VERSION 5.7 ;
  NOWIREEXTENSIONATPIN ON ;
  DIVIDERCHAR "/" ;
  BUSBITCHARS "[]" ;
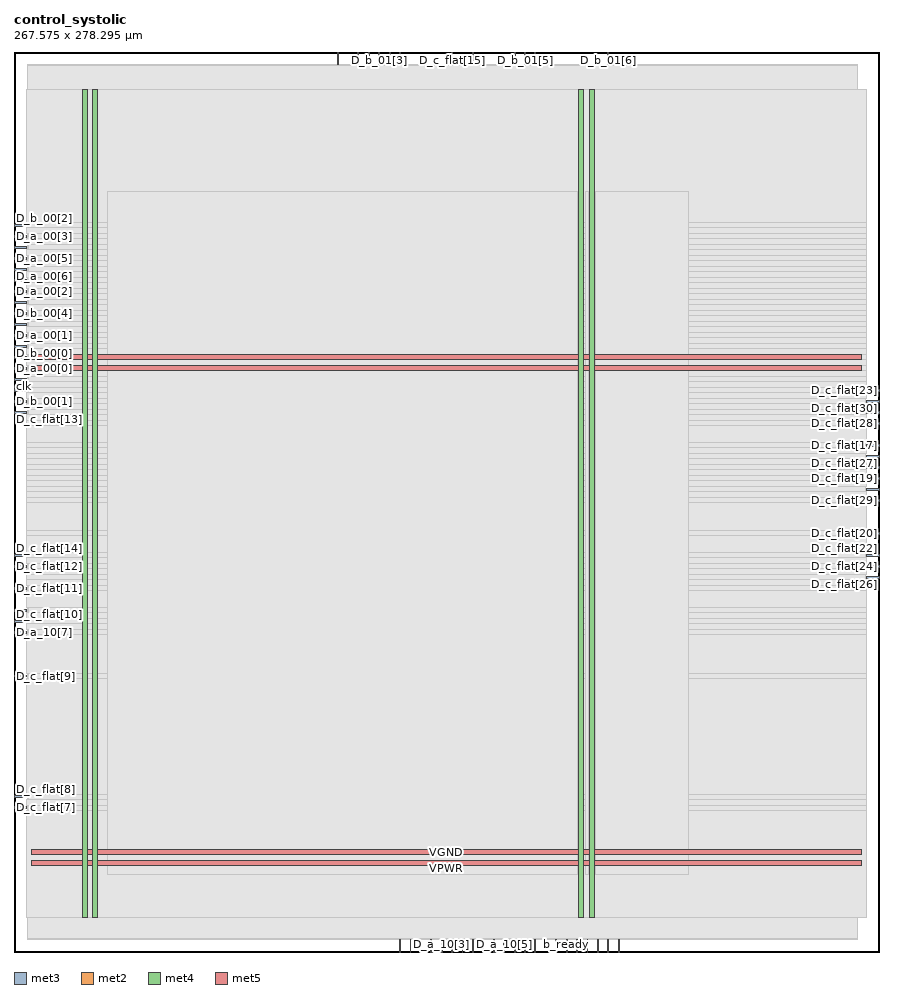
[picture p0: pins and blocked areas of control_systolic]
MACRO control_systolic
  CLASS BLOCK ;
  FOREIGN control_systolic ;
  ORIGIN 0.000 0.000 ;
  SIZE 267.575 BY 278.295 ;
  PIN D_a_00[0]
    DIRECTION INPUT ;
    USE SIGNAL ;
    ANTENNAGATEAREA 0.196500 ;
    PORT
      LAYER met3 ;
        RECT 0.000 180.240 4.000 180.840 ;
    END
  END D_a_00[0]
  PIN D_a_00[1]
    DIRECTION INPUT ;
    USE SIGNAL ;
    ANTENNAGATEAREA 0.196500 ;
    PORT
      LAYER met3 ;
        RECT 0.000 190.440 4.000 191.040 ;
    END
  END D_a_00[1]
  PIN D_a_00[2]
    DIRECTION INPUT ;
    USE SIGNAL ;
    ANTENNAGATEAREA 0.196500 ;
    PORT
      LAYER met3 ;
        RECT 0.000 204.040 4.000 204.640 ;
    END
  END D_a_00[2]
  PIN D_a_00[3]
    DIRECTION INPUT ;
    USE SIGNAL ;
    ANTENNAGATEAREA 0.196500 ;
    PORT
      LAYER met3 ;
        RECT 0.000 221.040 4.000 221.640 ;
    END
  END D_a_00[3]
  PIN D_a_00[4]
    DIRECTION INPUT ;
    USE SIGNAL ;
    ANTENNAGATEAREA 0.196500 ;
    PORT
      LAYER met3 ;
        RECT 0.000 217.640 4.000 218.240 ;
    END
  END D_a_00[4]
  PIN D_a_00[5]
    DIRECTION INPUT ;
    USE SIGNAL ;
    ANTENNAGATEAREA 0.196500 ;
    PORT
      LAYER met3 ;
        RECT 0.000 214.240 4.000 214.840 ;
    END
  END D_a_00[5]
  PIN D_a_00[6]
    DIRECTION INPUT ;
    USE SIGNAL ;
    ANTENNAGATEAREA 0.196500 ;
    PORT
      LAYER met3 ;
        RECT 0.000 210.840 4.000 211.440 ;
    END
  END D_a_00[6]
  PIN D_a_00[7]
    DIRECTION INPUT ;
    USE SIGNAL ;
    ANTENNAGATEAREA 0.196500 ;
    PORT
      LAYER met2 ;
        RECT 99.910 274.295 100.190 278.295 ;
    END
  END D_a_00[7]
  PIN D_a_10[0]
    DIRECTION INPUT ;
    USE SIGNAL ;
    ANTENNAGATEAREA 0.196500 ;
    PORT
      LAYER met2 ;
        RECT 148.210 0.000 148.490 4.000 ;
    END
  END D_a_10[0]
  PIN D_a_10[1]
    DIRECTION INPUT ;
    USE SIGNAL ;
    ANTENNAGATEAREA 0.196500 ;
    PORT
      LAYER met2 ;
        RECT 141.770 0.000 142.050 4.000 ;
    END
  END D_a_10[1]
  PIN D_a_10[2]
    DIRECTION INPUT ;
    USE SIGNAL ;
    ANTENNAGATEAREA 0.196500 ;
    PORT
      LAYER met2 ;
        RECT 128.890 0.000 129.170 4.000 ;
    END
  END D_a_10[2]
  PIN D_a_10[3]
    DIRECTION INPUT ;
    USE SIGNAL ;
    ANTENNAGATEAREA 0.196500 ;
    PORT
      LAYER met2 ;
        RECT 132.110 0.000 132.390 4.000 ;
    END
  END D_a_10[3]
  PIN D_a_10[4]
    DIRECTION INPUT ;
    USE SIGNAL ;
    ANTENNAGATEAREA 0.196500 ;
    PORT
      LAYER met2 ;
        RECT 135.330 0.000 135.610 4.000 ;
    END
  END D_a_10[4]
  PIN D_a_10[5]
    DIRECTION INPUT ;
    USE SIGNAL ;
    ANTENNAGATEAREA 0.196500 ;
    PORT
      LAYER met2 ;
        RECT 151.430 0.000 151.710 4.000 ;
    END
  END D_a_10[5]
  PIN D_a_10[6]
    DIRECTION INPUT ;
    USE SIGNAL ;
    ANTENNAGATEAREA 0.196500 ;
    PORT
      LAYER met2 ;
        RECT 157.870 0.000 158.150 4.000 ;
    END
  END D_a_10[6]
  PIN D_a_10[7]
    DIRECTION INPUT ;
    USE SIGNAL ;
    ANTENNAGATEAREA 0.196500 ;
    PORT
      LAYER met3 ;
        RECT 0.000 98.640 4.000 99.240 ;
    END
  END D_a_10[7]
  PIN D_b_00[0]
    DIRECTION INPUT ;
    USE SIGNAL ;
    ANTENNAGATEAREA 0.196500 ;
    PORT
      LAYER met3 ;
        RECT 0.000 187.040 4.000 187.640 ;
    END
  END D_b_00[0]
  PIN D_b_00[1]
    DIRECTION INPUT ;
    USE SIGNAL ;
    ANTENNAGATEAREA 0.196500 ;
    PORT
      LAYER met3 ;
        RECT 0.000 170.040 4.000 170.640 ;
    END
  END D_b_00[1]
  PIN D_b_00[2]
    DIRECTION INPUT ;
    USE SIGNAL ;
    ANTENNAGATEAREA 0.196500 ;
    PORT
      LAYER met3 ;
        RECT 0.000 224.440 4.000 225.040 ;
    END
  END D_b_00[2]
  PIN D_b_00[3]
    DIRECTION INPUT ;
    USE SIGNAL ;
    ANTENNAGATEAREA 0.196500 ;
    PORT
      LAYER met3 ;
        RECT 0.000 207.440 4.000 208.040 ;
    END
  END D_b_00[3]
  PIN D_b_00[4]
    DIRECTION INPUT ;
    USE SIGNAL ;
    ANTENNAGATEAREA 0.196500 ;
    PORT
      LAYER met3 ;
        RECT 0.000 197.240 4.000 197.840 ;
    END
  END D_b_00[4]
  PIN D_b_00[5]
    DIRECTION INPUT ;
    USE SIGNAL ;
    ANTENNAGATEAREA 0.196500 ;
    PORT
      LAYER met3 ;
        RECT 0.000 193.840 4.000 194.440 ;
    END
  END D_b_00[5]
  PIN D_b_00[6]
    DIRECTION INPUT ;
    USE SIGNAL ;
    ANTENNAGATEAREA 0.196500 ;
    PORT
      LAYER met3 ;
        RECT 0.000 183.640 4.000 184.240 ;
    END
  END D_b_00[6]
  PIN D_b_00[7]
    DIRECTION INPUT ;
    USE SIGNAL ;
    ANTENNAGATEAREA 0.196500 ;
    PORT
      LAYER met3 ;
        RECT 0.000 200.640 4.000 201.240 ;
    END
  END D_b_00[7]
  PIN D_b_01[0]
    DIRECTION INPUT ;
    USE SIGNAL ;
    ANTENNAGATEAREA 0.196500 ;
    PORT
      LAYER met2 ;
        RECT 109.570 274.295 109.850 278.295 ;
    END
  END D_b_01[0]
  PIN D_b_01[1]
    DIRECTION INPUT ;
    USE SIGNAL ;
    ANTENNAGATEAREA 0.196500 ;
    PORT
      LAYER met2 ;
        RECT 106.350 274.295 106.630 278.295 ;
    END
  END D_b_01[1]
  PIN D_b_01[2]
    DIRECTION INPUT ;
    USE SIGNAL ;
    ANTENNAGATEAREA 0.196500 ;
    PORT
      LAYER met2 ;
        RECT 119.230 274.295 119.510 278.295 ;
    END
  END D_b_01[2]
  PIN D_b_01[3]
    DIRECTION INPUT ;
    USE SIGNAL ;
    ANTENNAGATEAREA 0.196500 ;
    PORT
      LAYER met2 ;
        RECT 112.790 274.295 113.070 278.295 ;
    END
  END D_b_01[3]
  PIN D_b_01[4]
    DIRECTION INPUT ;
    USE SIGNAL ;
    ANTENNAGATEAREA 0.196500 ;
    PORT
      LAYER met2 ;
        RECT 116.010 274.295 116.290 278.295 ;
    END
  END D_b_01[4]
  PIN D_b_01[5]
    DIRECTION INPUT ;
    USE SIGNAL ;
    ANTENNAGATEAREA 0.196500 ;
    PORT
      LAYER met2 ;
        RECT 157.870 274.295 158.150 278.295 ;
    END
  END D_b_01[5]
  PIN D_b_01[6]
    DIRECTION INPUT ;
    USE SIGNAL ;
    ANTENNAGATEAREA 0.196500 ;
    PORT
      LAYER met2 ;
        RECT 183.630 274.295 183.910 278.295 ;
    END
  END D_b_01[6]
  PIN D_b_01[7]
    DIRECTION INPUT ;
    USE SIGNAL ;
    ANTENNAGATEAREA 0.196500 ;
    PORT
      LAYER met2 ;
        RECT 154.650 274.295 154.930 278.295 ;
    END
  END D_b_01[7]
  PIN D_c_flat[0]
    DIRECTION OUTPUT ;
    USE SIGNAL ;
    ANTENNADIFFAREA 0.445500 ;
    PORT
      LAYER met2 ;
        RECT 138.550 0.000 138.830 4.000 ;
    END
  END D_c_flat[0]
  PIN D_c_flat[10]
    DIRECTION OUTPUT ;
    USE SIGNAL ;
    ANTENNADIFFAREA 0.445500 ;
    PORT
      LAYER met3 ;
        RECT 0.000 102.040 4.000 102.640 ;
    END
  END D_c_flat[10]
  PIN D_c_flat[11]
    DIRECTION OUTPUT ;
    USE SIGNAL ;
    ANTENNADIFFAREA 0.445500 ;
    PORT
      LAYER met3 ;
        RECT 0.000 112.240 4.000 112.840 ;
    END
  END D_c_flat[11]
  PIN D_c_flat[12]
    DIRECTION OUTPUT ;
    USE SIGNAL ;
    ANTENNADIFFAREA 0.445500 ;
    PORT
      LAYER met3 ;
        RECT 0.000 119.040 4.000 119.640 ;
    END
  END D_c_flat[12]
  PIN D_c_flat[13]
    DIRECTION OUTPUT ;
    USE SIGNAL ;
    ANTENNADIFFAREA 0.445500 ;
    PORT
      LAYER met3 ;
        RECT 0.000 166.640 4.000 167.240 ;
    END
  END D_c_flat[13]
  PIN D_c_flat[14]
    DIRECTION OUTPUT ;
    USE SIGNAL ;
    ANTENNADIFFAREA 0.445500 ;
    PORT
      LAYER met3 ;
        RECT 0.000 122.440 4.000 123.040 ;
    END
  END D_c_flat[14]
  PIN D_c_flat[15]
    DIRECTION OUTPUT ;
    USE SIGNAL ;
    ANTENNADIFFAREA 0.445500 ;
    PORT
      LAYER met2 ;
        RECT 135.330 274.295 135.610 278.295 ;
    END
  END D_c_flat[15]
  PIN D_c_flat[16]
    DIRECTION OUTPUT ;
    USE SIGNAL ;
    ANTENNADIFFAREA 0.445500 ;
    PORT
      LAYER met3 ;
        RECT 263.575 149.640 267.575 150.240 ;
    END
  END D_c_flat[16]
  PIN D_c_flat[17]
    DIRECTION OUTPUT ;
    USE SIGNAL ;
    ANTENNADIFFAREA 0.445500 ;
    PORT
      LAYER met3 ;
        RECT 263.575 156.440 267.575 157.040 ;
    END
  END D_c_flat[17]
  PIN D_c_flat[18]
    DIRECTION OUTPUT ;
    USE SIGNAL ;
    ANTENNADIFFAREA 0.445500 ;
    PORT
      LAYER met2 ;
        RECT 141.770 274.295 142.050 278.295 ;
    END
  END D_c_flat[18]
  PIN D_c_flat[19]
    DIRECTION OUTPUT ;
    USE SIGNAL ;
    ANTENNADIFFAREA 0.445500 ;
    PORT
      LAYER met3 ;
        RECT 263.575 146.240 267.575 146.840 ;
    END
  END D_c_flat[19]
  PIN D_c_flat[1]
    DIRECTION OUTPUT ;
    USE SIGNAL ;
    ANTENNADIFFAREA 0.445500 ;
    PORT
      LAYER met2 ;
        RECT 144.990 0.000 145.270 4.000 ;
    END
  END D_c_flat[1]
  PIN D_c_flat[20]
    DIRECTION OUTPUT ;
    USE SIGNAL ;
    ANTENNADIFFAREA 0.445500 ;
    PORT
      LAYER met3 ;
        RECT 263.575 129.240 267.575 129.840 ;
    END
  END D_c_flat[20]
  PIN D_c_flat[21]
    DIRECTION OUTPUT ;
    USE SIGNAL ;
    ANTENNADIFFAREA 0.445500 ;
    PORT
      LAYER met2 ;
        RECT 161.090 274.295 161.370 278.295 ;
    END
  END D_c_flat[21]
  PIN D_c_flat[22]
    DIRECTION OUTPUT ;
    USE SIGNAL ;
    ANTENNADIFFAREA 0.445500 ;
    PORT
      LAYER met3 ;
        RECT 263.575 122.440 267.575 123.040 ;
    END
  END D_c_flat[22]
  PIN D_c_flat[23]
    DIRECTION OUTPUT ;
    USE SIGNAL ;
    ANTENNADIFFAREA 0.445500 ;
    PORT
      LAYER met3 ;
        RECT 263.575 173.440 267.575 174.040 ;
    END
  END D_c_flat[23]
  PIN D_c_flat[24]
    DIRECTION OUTPUT ;
    USE SIGNAL ;
    ANTENNADIFFAREA 0.445500 ;
    PORT
      LAYER met3 ;
        RECT 263.575 119.040 267.575 119.640 ;
    END
  END D_c_flat[24]
  PIN D_c_flat[25]
    DIRECTION OUTPUT ;
    USE SIGNAL ;
    ANTENNADIFFAREA 0.445500 ;
    PORT
      LAYER met3 ;
        RECT 263.575 166.640 267.575 167.240 ;
    END
  END D_c_flat[25]
  PIN D_c_flat[26]
    DIRECTION OUTPUT ;
    USE SIGNAL ;
    ANTENNADIFFAREA 0.445500 ;
    PORT
      LAYER met3 ;
        RECT 263.575 115.640 267.575 116.240 ;
    END
  END D_c_flat[26]
  PIN D_c_flat[27]
    DIRECTION OUTPUT ;
    USE SIGNAL ;
    ANTENNADIFFAREA 0.445500 ;
    PORT
      LAYER met3 ;
        RECT 263.575 153.040 267.575 153.640 ;
    END
  END D_c_flat[27]
  PIN D_c_flat[28]
    DIRECTION OUTPUT ;
    USE SIGNAL ;
    ANTENNADIFFAREA 0.445500 ;
    PORT
      LAYER met3 ;
        RECT 263.575 163.240 267.575 163.840 ;
    END
  END D_c_flat[28]
  PIN D_c_flat[29]
    DIRECTION OUTPUT ;
    USE SIGNAL ;
    ANTENNADIFFAREA 0.445500 ;
    PORT
      LAYER met3 ;
        RECT 263.575 139.440 267.575 140.040 ;
    END
  END D_c_flat[29]
  PIN D_c_flat[2]
    DIRECTION OUTPUT ;
    USE SIGNAL ;
    ANTENNADIFFAREA 0.445500 ;
    PORT
      LAYER met2 ;
        RECT 161.090 0.000 161.370 4.000 ;
    END
  END D_c_flat[2]
  PIN D_c_flat[30]
    DIRECTION OUTPUT ;
    USE SIGNAL ;
    ANTENNADIFFAREA 0.445500 ;
    PORT
      LAYER met3 ;
        RECT 263.575 170.040 267.575 170.640 ;
    END
  END D_c_flat[30]
  PIN D_c_flat[31]
    DIRECTION OUTPUT ;
    USE SIGNAL ;
    ANTENNADIFFAREA 0.445500 ;
    PORT
      LAYER met3 ;
        RECT 263.575 142.840 267.575 143.440 ;
    END
  END D_c_flat[31]
  PIN D_c_flat[3]
    DIRECTION OUTPUT ;
    USE SIGNAL ;
    ANTENNADIFFAREA 0.445500 ;
    PORT
      LAYER met2 ;
        RECT 154.650 0.000 154.930 4.000 ;
    END
  END D_c_flat[3]
  PIN D_c_flat[4]
    DIRECTION OUTPUT ;
    USE SIGNAL ;
    ANTENNADIFFAREA 0.445500 ;
    PORT
      LAYER met2 ;
        RECT 122.450 0.000 122.730 4.000 ;
    END
  END D_c_flat[4]
  PIN D_c_flat[5]
    DIRECTION OUTPUT ;
    USE SIGNAL ;
    ANTENNADIFFAREA 0.445500 ;
    PORT
      LAYER met2 ;
        RECT 119.230 0.000 119.510 4.000 ;
    END
  END D_c_flat[5]
  PIN D_c_flat[6]
    DIRECTION OUTPUT ;
    USE SIGNAL ;
    ANTENNADIFFAREA 0.445500 ;
    PORT
      LAYER met3 ;
        RECT 0.000 105.440 4.000 106.040 ;
    END
  END D_c_flat[6]
  PIN D_c_flat[7]
    DIRECTION OUTPUT ;
    USE SIGNAL ;
    ANTENNADIFFAREA 0.445500 ;
    PORT
      LAYER met3 ;
        RECT 0.000 44.240 4.000 44.840 ;
    END
  END D_c_flat[7]
  PIN D_c_flat[8]
    DIRECTION OUTPUT ;
    USE SIGNAL ;
    ANTENNADIFFAREA 0.445500 ;
    PORT
      LAYER met3 ;
        RECT 0.000 47.640 4.000 48.240 ;
    END
  END D_c_flat[8]
  PIN D_c_flat[9]
    DIRECTION OUTPUT ;
    USE SIGNAL ;
    ANTENNADIFFAREA 0.445500 ;
    PORT
      LAYER met3 ;
        RECT 0.000 85.040 4.000 85.640 ;
    END
  END D_c_flat[9]
  PIN VGND
    DIRECTION INOUT ;
    USE GROUND ;
    PORT
      LAYER met4 ;
        RECT 24.340 10.640 25.940 266.800 ;
    END
    PORT
      LAYER met4 ;
        RECT 177.940 10.640 179.540 266.800 ;
    END
    PORT
      LAYER met5 ;
        RECT 5.280 30.030 261.980 31.630 ;
    END
    PORT
      LAYER met5 ;
        RECT 5.280 183.210 261.980 184.810 ;
    END
  END VGND
  PIN VPWR
    DIRECTION INOUT ;
    USE POWER ;
    PORT
      LAYER met4 ;
        RECT 21.040 10.640 22.640 266.800 ;
    END
    PORT
      LAYER met4 ;
        RECT 174.640 10.640 176.240 266.800 ;
    END
    PORT
      LAYER met5 ;
        RECT 5.280 26.730 261.980 28.330 ;
    END
    PORT
      LAYER met5 ;
        RECT 5.280 179.910 261.980 181.510 ;
    END
  END VPWR
  PIN a_ready
    DIRECTION INPUT ;
    USE SIGNAL ;
    ANTENNAGATEAREA 0.196500 ;
    PORT
      LAYER met2 ;
        RECT 167.530 0.000 167.810 4.000 ;
    END
  END a_ready
  PIN b_ready
    DIRECTION INPUT ;
    USE SIGNAL ;
    ANTENNAGATEAREA 0.196500 ;
    PORT
      LAYER met2 ;
        RECT 170.750 0.000 171.030 4.000 ;
    END
  END b_ready
  PIN clk
    DIRECTION INPUT ;
    USE SIGNAL ;
    ANTENNAGATEAREA 0.852000 ;
    PORT
      LAYER met3 ;
        RECT 0.000 176.840 4.000 177.440 ;
    END
  END clk
  PIN num_matrix[0]
    DIRECTION INPUT ;
    USE SIGNAL ;
    ANTENNAGATEAREA 0.196500 ;
    PORT
      LAYER met2 ;
        RECT 186.850 0.000 187.130 4.000 ;
    END
  END num_matrix[0]
  PIN num_matrix[1]
    DIRECTION INPUT ;
    USE SIGNAL ;
    ANTENNAGATEAREA 0.196500 ;
    PORT
      LAYER met2 ;
        RECT 173.970 0.000 174.250 4.000 ;
    END
  END num_matrix[1]
  PIN num_matrix[2]
    DIRECTION INPUT ;
    USE SIGNAL ;
    ANTENNAGATEAREA 0.196500 ;
    PORT
      LAYER met2 ;
        RECT 177.190 0.000 177.470 4.000 ;
    END
  END num_matrix[2]
  PIN rst
    DIRECTION INPUT ;
    USE SIGNAL ;
    ANTENNAGATEAREA 0.196500 ;
    PORT
      LAYER met3 ;
        RECT 0.000 173.440 4.000 174.040 ;
    END
  END rst
  PIN systolic_busy
    DIRECTION OUTPUT ;
    USE SIGNAL ;
    ANTENNADIFFAREA 0.445500 ;
    PORT
      LAYER met2 ;
        RECT 183.630 0.000 183.910 4.000 ;
    END
  END systolic_busy
  PIN systolic_free
    DIRECTION OUTPUT ;
    USE SIGNAL ;
    ANTENNADIFFAREA 0.445500 ;
    PORT
      LAYER met2 ;
        RECT 180.410 0.000 180.690 4.000 ;
    END
  END systolic_free
  OBS
      LAYER nwell ;
        RECT 5.330 10.795 261.930 266.645 ;
      LAYER li1 ;
        RECT 5.520 10.795 261.740 266.645 ;
      LAYER met1 ;
        RECT 4.210 10.640 262.040 266.800 ;
      LAYER met2 ;
        RECT 4.230 274.015 99.630 274.295 ;
        RECT 100.470 274.015 106.070 274.295 ;
        RECT 106.910 274.015 109.290 274.295 ;
        RECT 110.130 274.015 112.510 274.295 ;
        RECT 113.350 274.015 115.730 274.295 ;
        RECT 116.570 274.015 118.950 274.295 ;
        RECT 119.790 274.015 135.050 274.295 ;
        RECT 135.890 274.015 141.490 274.295 ;
        RECT 142.330 274.015 154.370 274.295 ;
        RECT 155.210 274.015 157.590 274.295 ;
        RECT 158.430 274.015 160.810 274.295 ;
        RECT 161.650 274.015 183.350 274.295 ;
        RECT 184.190 274.015 260.730 274.295 ;
        RECT 4.230 4.280 260.730 274.015 ;
        RECT 4.230 4.000 118.950 4.280 ;
        RECT 119.790 4.000 122.170 4.280 ;
        RECT 123.010 4.000 128.610 4.280 ;
        RECT 129.450 4.000 131.830 4.280 ;
        RECT 132.670 4.000 135.050 4.280 ;
        RECT 135.890 4.000 138.270 4.280 ;
        RECT 139.110 4.000 141.490 4.280 ;
        RECT 142.330 4.000 144.710 4.280 ;
        RECT 145.550 4.000 147.930 4.280 ;
        RECT 148.770 4.000 151.150 4.280 ;
        RECT 151.990 4.000 154.370 4.280 ;
        RECT 155.210 4.000 157.590 4.280 ;
        RECT 158.430 4.000 160.810 4.280 ;
        RECT 161.650 4.000 167.250 4.280 ;
        RECT 168.090 4.000 170.470 4.280 ;
        RECT 171.310 4.000 173.690 4.280 ;
        RECT 174.530 4.000 176.910 4.280 ;
        RECT 177.750 4.000 180.130 4.280 ;
        RECT 180.970 4.000 183.350 4.280 ;
        RECT 184.190 4.000 186.570 4.280 ;
        RECT 187.410 4.000 260.730 4.280 ;
      LAYER met3 ;
        RECT 3.990 225.440 263.575 266.725 ;
        RECT 4.400 224.040 263.575 225.440 ;
        RECT 3.990 222.040 263.575 224.040 ;
        RECT 4.400 220.640 263.575 222.040 ;
        RECT 3.990 218.640 263.575 220.640 ;
        RECT 4.400 217.240 263.575 218.640 ;
        RECT 3.990 215.240 263.575 217.240 ;
        RECT 4.400 213.840 263.575 215.240 ;
        RECT 3.990 211.840 263.575 213.840 ;
        RECT 4.400 210.440 263.575 211.840 ;
        RECT 3.990 208.440 263.575 210.440 ;
        RECT 4.400 207.040 263.575 208.440 ;
        RECT 3.990 205.040 263.575 207.040 ;
        RECT 4.400 203.640 263.575 205.040 ;
        RECT 3.990 201.640 263.575 203.640 ;
        RECT 4.400 200.240 263.575 201.640 ;
        RECT 3.990 198.240 263.575 200.240 ;
        RECT 4.400 196.840 263.575 198.240 ;
        RECT 3.990 194.840 263.575 196.840 ;
        RECT 4.400 193.440 263.575 194.840 ;
        RECT 3.990 191.440 263.575 193.440 ;
        RECT 4.400 190.040 263.575 191.440 ;
        RECT 3.990 188.040 263.575 190.040 ;
        RECT 4.400 186.640 263.575 188.040 ;
        RECT 3.990 184.640 263.575 186.640 ;
        RECT 4.400 183.240 263.575 184.640 ;
        RECT 3.990 181.240 263.575 183.240 ;
        RECT 4.400 179.840 263.575 181.240 ;
        RECT 3.990 177.840 263.575 179.840 ;
        RECT 4.400 176.440 263.575 177.840 ;
        RECT 3.990 174.440 263.575 176.440 ;
        RECT 4.400 173.040 263.175 174.440 ;
        RECT 3.990 171.040 263.575 173.040 ;
        RECT 4.400 169.640 263.175 171.040 ;
        RECT 3.990 167.640 263.575 169.640 ;
        RECT 4.400 166.240 263.175 167.640 ;
        RECT 3.990 164.240 263.575 166.240 ;
        RECT 3.990 162.840 263.175 164.240 ;
        RECT 3.990 157.440 263.575 162.840 ;
        RECT 3.990 156.040 263.175 157.440 ;
        RECT 3.990 154.040 263.575 156.040 ;
        RECT 3.990 152.640 263.175 154.040 ;
        RECT 3.990 150.640 263.575 152.640 ;
        RECT 3.990 149.240 263.175 150.640 ;
        RECT 3.990 147.240 263.575 149.240 ;
        RECT 3.990 145.840 263.175 147.240 ;
        RECT 3.990 143.840 263.575 145.840 ;
        RECT 3.990 142.440 263.175 143.840 ;
        RECT 3.990 140.440 263.575 142.440 ;
        RECT 3.990 139.040 263.175 140.440 ;
        RECT 3.990 130.240 263.575 139.040 ;
        RECT 3.990 128.840 263.175 130.240 ;
        RECT 3.990 123.440 263.575 128.840 ;
        RECT 4.400 122.040 263.175 123.440 ;
        RECT 3.990 120.040 263.575 122.040 ;
        RECT 4.400 118.640 263.175 120.040 ;
        RECT 3.990 116.640 263.575 118.640 ;
        RECT 3.990 115.240 263.175 116.640 ;
        RECT 3.990 113.240 263.575 115.240 ;
        RECT 4.400 111.840 263.575 113.240 ;
        RECT 3.990 106.440 263.575 111.840 ;
        RECT 4.400 105.040 263.575 106.440 ;
        RECT 3.990 103.040 263.575 105.040 ;
        RECT 4.400 101.640 263.575 103.040 ;
        RECT 3.990 99.640 263.575 101.640 ;
        RECT 4.400 98.240 263.575 99.640 ;
        RECT 3.990 86.040 263.575 98.240 ;
        RECT 4.400 84.640 263.575 86.040 ;
        RECT 3.990 48.640 263.575 84.640 ;
        RECT 4.400 47.240 263.575 48.640 ;
        RECT 3.990 45.240 263.575 47.240 ;
        RECT 4.400 43.840 263.575 45.240 ;
        RECT 3.990 10.715 263.575 43.840 ;
      LAYER met4 ;
        RECT 28.815 23.975 174.240 235.105 ;
        RECT 176.640 23.975 177.540 235.105 ;
        RECT 179.940 23.975 208.545 235.105 ;
  END
END control_systolic
END LIBRARY

